VERSION 5.7 ;
  NOWIREEXTENSIONATPIN ON ;
  DIVIDERCHAR "/" ;
  BUSBITCHARS "[]" ;
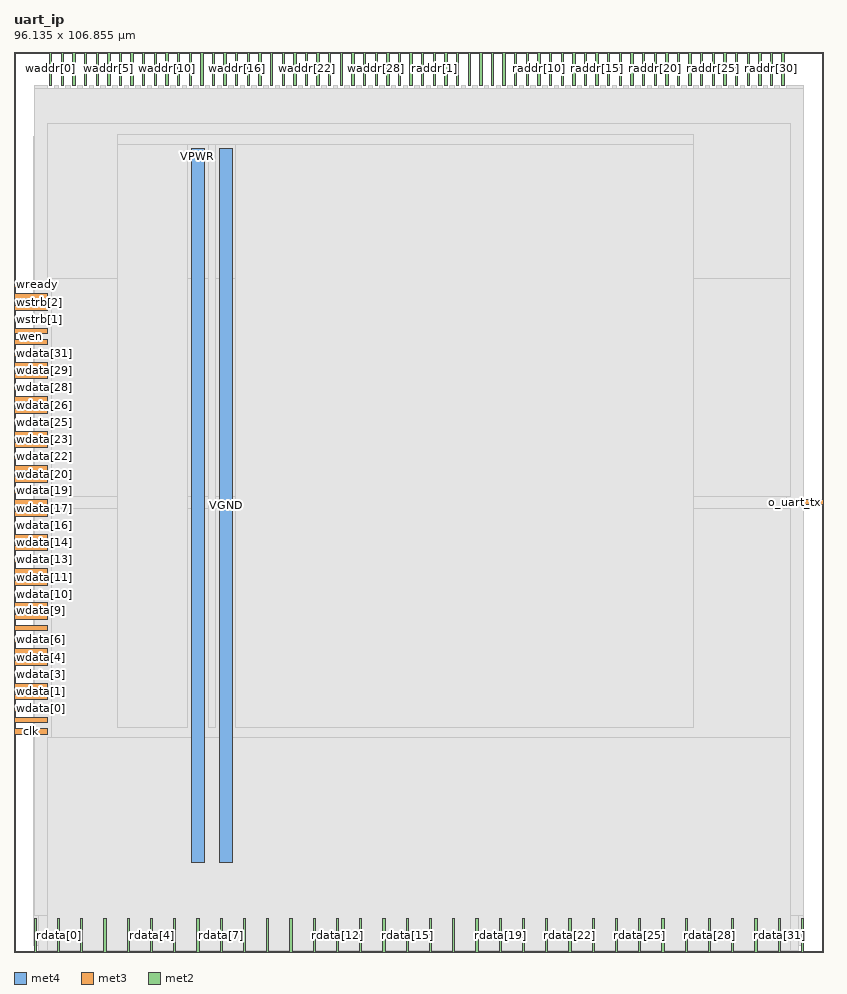
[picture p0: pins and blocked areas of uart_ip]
MACRO uart_ip
  CLASS BLOCK ;
  FOREIGN uart_ip ;
  ORIGIN 0.000 0.000 ;
  SIZE 96.135 BY 106.855 ;
  PIN VGND
    DIRECTION INOUT ;
    USE GROUND ;
    PORT
      LAYER met4 ;
        RECT 24.340 10.640 25.940 95.440 ;
    END
  END VGND
  PIN VPWR
    DIRECTION INOUT ;
    USE POWER ;
    PORT
      LAYER met4 ;
        RECT 21.040 10.640 22.640 95.440 ;
    END
  END VPWR
  PIN clk
    DIRECTION INPUT ;
    USE SIGNAL ;
    ANTENNAGATEAREA 1.286700 ;
    ANTENNADIFFAREA 0.434700 ;
    PORT
      LAYER met3 ;
        RECT 0.000 25.880 4.000 26.480 ;
    END
  END clk
  PIN o_uart_tx
    DIRECTION OUTPUT ;
    USE SIGNAL ;
    ANTENNAGATEAREA 0.434700 ;
    ANTENNADIFFAREA 0.880200 ;
    PORT
      LAYER met3 ;
        RECT 92.135 53.080 96.135 53.680 ;
    END
  END o_uart_tx
  PIN raddr[0]
    DIRECTION INPUT ;
    USE SIGNAL ;
    ANTENNAGATEAREA 0.631200 ;
    ANTENNADIFFAREA 0.434700 ;
    PORT
      LAYER met2 ;
        RECT 48.390 102.855 48.670 106.855 ;
    END
  END raddr[0]
  PIN raddr[10]
    DIRECTION INPUT ;
    USE SIGNAL ;
    ANTENNAGATEAREA 0.631200 ;
    ANTENNADIFFAREA 0.434700 ;
    PORT
      LAYER met2 ;
        RECT 62.190 102.855 62.470 106.855 ;
    END
  END raddr[10]
  PIN raddr[11]
    DIRECTION INPUT ;
    USE SIGNAL ;
    ANTENNAGATEAREA 0.631200 ;
    ANTENNADIFFAREA 0.434700 ;
    PORT
      LAYER met2 ;
        RECT 63.570 102.855 63.850 106.855 ;
    END
  END raddr[11]
  PIN raddr[12]
    DIRECTION INPUT ;
    USE SIGNAL ;
    ANTENNAGATEAREA 0.631200 ;
    ANTENNADIFFAREA 0.434700 ;
    PORT
      LAYER met2 ;
        RECT 64.950 102.855 65.230 106.855 ;
    END
  END raddr[12]
  PIN raddr[13]
    DIRECTION INPUT ;
    USE SIGNAL ;
    ANTENNAGATEAREA 0.631200 ;
    ANTENNADIFFAREA 0.434700 ;
    PORT
      LAYER met2 ;
        RECT 66.330 102.855 66.610 106.855 ;
    END
  END raddr[13]
  PIN raddr[14]
    DIRECTION INPUT ;
    USE SIGNAL ;
    ANTENNAGATEAREA 0.631200 ;
    ANTENNADIFFAREA 0.434700 ;
    PORT
      LAYER met2 ;
        RECT 67.710 102.855 67.990 106.855 ;
    END
  END raddr[14]
  PIN raddr[15]
    DIRECTION INPUT ;
    USE SIGNAL ;
    ANTENNAGATEAREA 0.631200 ;
    ANTENNADIFFAREA 0.434700 ;
    PORT
      LAYER met2 ;
        RECT 69.090 102.855 69.370 106.855 ;
    END
  END raddr[15]
  PIN raddr[16]
    DIRECTION INPUT ;
    USE SIGNAL ;
    ANTENNAGATEAREA 0.560700 ;
    ANTENNADIFFAREA 0.434700 ;
    PORT
      LAYER met2 ;
        RECT 70.470 102.855 70.750 106.855 ;
    END
  END raddr[16]
  PIN raddr[17]
    DIRECTION INPUT ;
    USE SIGNAL ;
    ANTENNAGATEAREA 0.631200 ;
    ANTENNADIFFAREA 0.434700 ;
    PORT
      LAYER met2 ;
        RECT 71.850 102.855 72.130 106.855 ;
    END
  END raddr[17]
  PIN raddr[18]
    DIRECTION INPUT ;
    USE SIGNAL ;
    ANTENNAGATEAREA 0.631200 ;
    ANTENNADIFFAREA 0.434700 ;
    PORT
      LAYER met2 ;
        RECT 73.230 102.855 73.510 106.855 ;
    END
  END raddr[18]
  PIN raddr[19]
    DIRECTION INPUT ;
    USE SIGNAL ;
    ANTENNAGATEAREA 0.631200 ;
    ANTENNADIFFAREA 0.434700 ;
    PORT
      LAYER met2 ;
        RECT 74.610 102.855 74.890 106.855 ;
    END
  END raddr[19]
  PIN raddr[1]
    DIRECTION INPUT ;
    USE SIGNAL ;
    ANTENNAGATEAREA 0.631200 ;
    ANTENNADIFFAREA 0.434700 ;
    PORT
      LAYER met2 ;
        RECT 49.770 102.855 50.050 106.855 ;
    END
  END raddr[1]
  PIN raddr[20]
    DIRECTION INPUT ;
    USE SIGNAL ;
    ANTENNAGATEAREA 0.631200 ;
    ANTENNADIFFAREA 0.434700 ;
    PORT
      LAYER met2 ;
        RECT 75.990 102.855 76.270 106.855 ;
    END
  END raddr[20]
  PIN raddr[21]
    DIRECTION INPUT ;
    USE SIGNAL ;
    ANTENNAGATEAREA 0.631200 ;
    ANTENNADIFFAREA 0.434700 ;
    PORT
      LAYER met2 ;
        RECT 77.370 102.855 77.650 106.855 ;
    END
  END raddr[21]
  PIN raddr[22]
    DIRECTION INPUT ;
    USE SIGNAL ;
    ANTENNAGATEAREA 0.631200 ;
    ANTENNADIFFAREA 0.434700 ;
    PORT
      LAYER met2 ;
        RECT 78.750 102.855 79.030 106.855 ;
    END
  END raddr[22]
  PIN raddr[23]
    DIRECTION INPUT ;
    USE SIGNAL ;
    ANTENNAGATEAREA 0.631200 ;
    ANTENNADIFFAREA 0.434700 ;
    PORT
      LAYER met2 ;
        RECT 80.130 102.855 80.410 106.855 ;
    END
  END raddr[23]
  PIN raddr[24]
    DIRECTION INPUT ;
    USE SIGNAL ;
    ANTENNAGATEAREA 0.631200 ;
    ANTENNADIFFAREA 0.434700 ;
    PORT
      LAYER met2 ;
        RECT 81.510 102.855 81.790 106.855 ;
    END
  END raddr[24]
  PIN raddr[25]
    DIRECTION INPUT ;
    USE SIGNAL ;
    ANTENNAGATEAREA 0.631200 ;
    ANTENNADIFFAREA 0.434700 ;
    PORT
      LAYER met2 ;
        RECT 82.890 102.855 83.170 106.855 ;
    END
  END raddr[25]
  PIN raddr[26]
    DIRECTION INPUT ;
    USE SIGNAL ;
    ANTENNAGATEAREA 0.631200 ;
    ANTENNADIFFAREA 0.434700 ;
    PORT
      LAYER met2 ;
        RECT 84.270 102.855 84.550 106.855 ;
    END
  END raddr[26]
  PIN raddr[27]
    DIRECTION INPUT ;
    USE SIGNAL ;
    ANTENNAGATEAREA 0.631200 ;
    ANTENNADIFFAREA 0.434700 ;
    PORT
      LAYER met2 ;
        RECT 85.650 102.855 85.930 106.855 ;
    END
  END raddr[27]
  PIN raddr[28]
    DIRECTION INPUT ;
    USE SIGNAL ;
    ANTENNAGATEAREA 0.631200 ;
    ANTENNADIFFAREA 0.434700 ;
    PORT
      LAYER met2 ;
        RECT 87.030 102.855 87.310 106.855 ;
    END
  END raddr[28]
  PIN raddr[29]
    DIRECTION INPUT ;
    USE SIGNAL ;
    ANTENNAGATEAREA 0.631200 ;
    ANTENNADIFFAREA 0.434700 ;
    PORT
      LAYER met2 ;
        RECT 88.410 102.855 88.690 106.855 ;
    END
  END raddr[29]
  PIN raddr[2]
    DIRECTION INPUT ;
    USE SIGNAL ;
    ANTENNAGATEAREA 0.560700 ;
    ANTENNADIFFAREA 0.434700 ;
    PORT
      LAYER met2 ;
        RECT 51.150 102.855 51.430 106.855 ;
    END
  END raddr[2]
  PIN raddr[30]
    DIRECTION INPUT ;
    USE SIGNAL ;
    ANTENNAGATEAREA 0.631200 ;
    ANTENNADIFFAREA 0.434700 ;
    PORT
      LAYER met2 ;
        RECT 89.790 102.855 90.070 106.855 ;
    END
  END raddr[30]
  PIN raddr[31]
    DIRECTION INPUT ;
    USE SIGNAL ;
    ANTENNAGATEAREA 0.631200 ;
    ANTENNADIFFAREA 0.434700 ;
    PORT
      LAYER met2 ;
        RECT 91.170 102.855 91.450 106.855 ;
    END
  END raddr[31]
  PIN raddr[3]
    DIRECTION INPUT ;
    USE SIGNAL ;
    ANTENNAGATEAREA 0.631200 ;
    ANTENNADIFFAREA 0.434700 ;
    PORT
      LAYER met2 ;
        RECT 52.530 102.855 52.810 106.855 ;
    END
  END raddr[3]
  PIN raddr[4]
    DIRECTION INPUT ;
    USE SIGNAL ;
    ANTENNAGATEAREA 0.631200 ;
    ANTENNADIFFAREA 0.434700 ;
    PORT
      LAYER met2 ;
        RECT 53.910 102.855 54.190 106.855 ;
    END
  END raddr[4]
  PIN raddr[5]
    DIRECTION INPUT ;
    USE SIGNAL ;
    ANTENNAGATEAREA 0.631200 ;
    ANTENNADIFFAREA 0.434700 ;
    PORT
      LAYER met2 ;
        RECT 55.290 102.855 55.570 106.855 ;
    END
  END raddr[5]
  PIN raddr[6]
    DIRECTION INPUT ;
    USE SIGNAL ;
    ANTENNAGATEAREA 0.631200 ;
    ANTENNADIFFAREA 0.434700 ;
    PORT
      LAYER met2 ;
        RECT 56.670 102.855 56.950 106.855 ;
    END
  END raddr[6]
  PIN raddr[7]
    DIRECTION INPUT ;
    USE SIGNAL ;
    ANTENNAGATEAREA 0.631200 ;
    ANTENNADIFFAREA 0.434700 ;
    PORT
      LAYER met2 ;
        RECT 58.050 102.855 58.330 106.855 ;
    END
  END raddr[7]
  PIN raddr[8]
    DIRECTION INPUT ;
    USE SIGNAL ;
    ANTENNAGATEAREA 0.560700 ;
    ANTENNADIFFAREA 0.434700 ;
    PORT
      LAYER met2 ;
        RECT 59.430 102.855 59.710 106.855 ;
    END
  END raddr[8]
  PIN raddr[9]
    DIRECTION INPUT ;
    USE SIGNAL ;
    ANTENNAGATEAREA 0.631200 ;
    ANTENNADIFFAREA 0.434700 ;
    PORT
      LAYER met2 ;
        RECT 60.810 102.855 61.090 106.855 ;
    END
  END raddr[9]
  PIN rdata[0]
    DIRECTION OUTPUT ;
    USE SIGNAL ;
    ANTENNAGATEAREA 0.434700 ;
    ANTENNADIFFAREA 0.880200 ;
    PORT
      LAYER met2 ;
        RECT 5.150 0.000 5.430 4.000 ;
    END
  END rdata[0]
  PIN rdata[10]
    DIRECTION OUTPUT ;
    USE SIGNAL ;
    ANTENNAGATEAREA 0.434700 ;
    ANTENNADIFFAREA 0.434700 ;
    PORT
      LAYER met2 ;
        RECT 32.750 0.000 33.030 4.000 ;
    END
  END rdata[10]
  PIN rdata[11]
    DIRECTION OUTPUT ;
    USE SIGNAL ;
    ANTENNAGATEAREA 0.434700 ;
    ANTENNADIFFAREA 0.434700 ;
    PORT
      LAYER met2 ;
        RECT 35.510 0.000 35.790 4.000 ;
    END
  END rdata[11]
  PIN rdata[12]
    DIRECTION OUTPUT ;
    USE SIGNAL ;
    ANTENNAGATEAREA 0.434700 ;
    ANTENNADIFFAREA 0.434700 ;
    PORT
      LAYER met2 ;
        RECT 38.270 0.000 38.550 4.000 ;
    END
  END rdata[12]
  PIN rdata[13]
    DIRECTION OUTPUT ;
    USE SIGNAL ;
    ANTENNAGATEAREA 0.434700 ;
    ANTENNADIFFAREA 0.880200 ;
    PORT
      LAYER met2 ;
        RECT 41.030 0.000 41.310 4.000 ;
    END
  END rdata[13]
  PIN rdata[14]
    DIRECTION OUTPUT ;
    USE SIGNAL ;
    ANTENNAGATEAREA 0.434700 ;
    ANTENNADIFFAREA 0.434700 ;
    PORT
      LAYER met2 ;
        RECT 43.790 0.000 44.070 4.000 ;
    END
  END rdata[14]
  PIN rdata[15]
    DIRECTION OUTPUT ;
    USE SIGNAL ;
    ANTENNAGATEAREA 0.434700 ;
    ANTENNADIFFAREA 0.434700 ;
    PORT
      LAYER met2 ;
        RECT 46.550 0.000 46.830 4.000 ;
    END
  END rdata[15]
  PIN rdata[16]
    DIRECTION OUTPUT ;
    USE SIGNAL ;
    ANTENNAGATEAREA 0.434700 ;
    ANTENNADIFFAREA 0.434700 ;
    PORT
      LAYER met2 ;
        RECT 49.310 0.000 49.590 4.000 ;
    END
  END rdata[16]
  PIN rdata[17]
    DIRECTION OUTPUT ;
    USE SIGNAL ;
    ANTENNAGATEAREA 0.434700 ;
    ANTENNADIFFAREA 0.434700 ;
    PORT
      LAYER met2 ;
        RECT 52.070 0.000 52.350 4.000 ;
    END
  END rdata[17]
  PIN rdata[18]
    DIRECTION OUTPUT ;
    USE SIGNAL ;
    ANTENNAGATEAREA 0.434700 ;
    ANTENNADIFFAREA 0.434700 ;
    PORT
      LAYER met2 ;
        RECT 54.830 0.000 55.110 4.000 ;
    END
  END rdata[18]
  PIN rdata[19]
    DIRECTION OUTPUT ;
    USE SIGNAL ;
    ANTENNAGATEAREA 0.434700 ;
    ANTENNADIFFAREA 0.434700 ;
    PORT
      LAYER met2 ;
        RECT 57.590 0.000 57.870 4.000 ;
    END
  END rdata[19]
  PIN rdata[1]
    DIRECTION OUTPUT ;
    USE SIGNAL ;
    ANTENNAGATEAREA 0.434700 ;
    ANTENNADIFFAREA 0.880200 ;
    PORT
      LAYER met2 ;
        RECT 7.910 0.000 8.190 4.000 ;
    END
  END rdata[1]
  PIN rdata[20]
    DIRECTION OUTPUT ;
    USE SIGNAL ;
    ANTENNAGATEAREA 0.434700 ;
    ANTENNADIFFAREA 0.434700 ;
    PORT
      LAYER met2 ;
        RECT 60.350 0.000 60.630 4.000 ;
    END
  END rdata[20]
  PIN rdata[21]
    DIRECTION OUTPUT ;
    USE SIGNAL ;
    ANTENNAGATEAREA 0.434700 ;
    ANTENNADIFFAREA 0.434700 ;
    PORT
      LAYER met2 ;
        RECT 63.110 0.000 63.390 4.000 ;
    END
  END rdata[21]
  PIN rdata[22]
    DIRECTION OUTPUT ;
    USE SIGNAL ;
    ANTENNAGATEAREA 0.434700 ;
    ANTENNADIFFAREA 0.434700 ;
    PORT
      LAYER met2 ;
        RECT 65.870 0.000 66.150 4.000 ;
    END
  END rdata[22]
  PIN rdata[23]
    DIRECTION OUTPUT ;
    USE SIGNAL ;
    ANTENNAGATEAREA 0.434700 ;
    ANTENNADIFFAREA 0.434700 ;
    PORT
      LAYER met2 ;
        RECT 68.630 0.000 68.910 4.000 ;
    END
  END rdata[23]
  PIN rdata[24]
    DIRECTION OUTPUT ;
    USE SIGNAL ;
    ANTENNAGATEAREA 0.434700 ;
    ANTENNADIFFAREA 0.434700 ;
    PORT
      LAYER met2 ;
        RECT 71.390 0.000 71.670 4.000 ;
    END
  END rdata[24]
  PIN rdata[25]
    DIRECTION OUTPUT ;
    USE SIGNAL ;
    ANTENNAGATEAREA 0.434700 ;
    ANTENNADIFFAREA 0.434700 ;
    PORT
      LAYER met2 ;
        RECT 74.150 0.000 74.430 4.000 ;
    END
  END rdata[25]
  PIN rdata[26]
    DIRECTION OUTPUT ;
    USE SIGNAL ;
    ANTENNAGATEAREA 0.434700 ;
    ANTENNADIFFAREA 0.434700 ;
    PORT
      LAYER met2 ;
        RECT 76.910 0.000 77.190 4.000 ;
    END
  END rdata[26]
  PIN rdata[27]
    DIRECTION OUTPUT ;
    USE SIGNAL ;
    ANTENNAGATEAREA 0.434700 ;
    ANTENNADIFFAREA 0.434700 ;
    PORT
      LAYER met2 ;
        RECT 79.670 0.000 79.950 4.000 ;
    END
  END rdata[27]
  PIN rdata[28]
    DIRECTION OUTPUT ;
    USE SIGNAL ;
    ANTENNAGATEAREA 0.434700 ;
    ANTENNADIFFAREA 0.434700 ;
    PORT
      LAYER met2 ;
        RECT 82.430 0.000 82.710 4.000 ;
    END
  END rdata[28]
  PIN rdata[29]
    DIRECTION OUTPUT ;
    USE SIGNAL ;
    ANTENNAGATEAREA 0.434700 ;
    ANTENNADIFFAREA 0.434700 ;
    PORT
      LAYER met2 ;
        RECT 85.190 0.000 85.470 4.000 ;
    END
  END rdata[29]
  PIN rdata[2]
    DIRECTION OUTPUT ;
    USE SIGNAL ;
    ANTENNAGATEAREA 0.434700 ;
    ANTENNADIFFAREA 0.880200 ;
    PORT
      LAYER met2 ;
        RECT 10.670 0.000 10.950 4.000 ;
    END
  END rdata[2]
  PIN rdata[30]
    DIRECTION OUTPUT ;
    USE SIGNAL ;
    ANTENNAGATEAREA 0.434700 ;
    ANTENNADIFFAREA 0.434700 ;
    PORT
      LAYER met2 ;
        RECT 87.950 0.000 88.230 4.000 ;
    END
  END rdata[30]
  PIN rdata[31]
    DIRECTION OUTPUT ;
    USE SIGNAL ;
    ANTENNAGATEAREA 0.434700 ;
    ANTENNADIFFAREA 0.434700 ;
    PORT
      LAYER met2 ;
        RECT 90.710 0.000 90.990 4.000 ;
    END
  END rdata[31]
  PIN rdata[3]
    DIRECTION OUTPUT ;
    USE SIGNAL ;
    ANTENNAGATEAREA 0.434700 ;
    ANTENNADIFFAREA 0.880200 ;
    PORT
      LAYER met2 ;
        RECT 13.430 0.000 13.710 4.000 ;
    END
  END rdata[3]
  PIN rdata[4]
    DIRECTION OUTPUT ;
    USE SIGNAL ;
    ANTENNAGATEAREA 0.434700 ;
    ANTENNADIFFAREA 0.880200 ;
    PORT
      LAYER met2 ;
        RECT 16.190 0.000 16.470 4.000 ;
    END
  END rdata[4]
  PIN rdata[5]
    DIRECTION OUTPUT ;
    USE SIGNAL ;
    ANTENNAGATEAREA 0.434700 ;
    ANTENNADIFFAREA 0.880200 ;
    PORT
      LAYER met2 ;
        RECT 18.950 0.000 19.230 4.000 ;
    END
  END rdata[5]
  PIN rdata[6]
    DIRECTION OUTPUT ;
    USE SIGNAL ;
    ANTENNAGATEAREA 0.434700 ;
    ANTENNADIFFAREA 0.880200 ;
    PORT
      LAYER met2 ;
        RECT 21.710 0.000 21.990 4.000 ;
    END
  END rdata[6]
  PIN rdata[7]
    DIRECTION OUTPUT ;
    USE SIGNAL ;
    ANTENNAGATEAREA 0.434700 ;
    ANTENNADIFFAREA 0.880200 ;
    PORT
      LAYER met2 ;
        RECT 24.470 0.000 24.750 4.000 ;
    END
  END rdata[7]
  PIN rdata[8]
    DIRECTION OUTPUT ;
    USE SIGNAL ;
    ANTENNAGATEAREA 0.434700 ;
    ANTENNADIFFAREA 0.434700 ;
    PORT
      LAYER met2 ;
        RECT 27.230 0.000 27.510 4.000 ;
    END
  END rdata[8]
  PIN rdata[9]
    DIRECTION OUTPUT ;
    USE SIGNAL ;
    ANTENNAGATEAREA 0.434700 ;
    ANTENNADIFFAREA 0.434700 ;
    PORT
      LAYER met2 ;
        RECT 29.990 0.000 30.270 4.000 ;
    END
  END rdata[9]
  PIN ren
    DIRECTION INPUT ;
    USE SIGNAL ;
    ANTENNAGATEAREA 0.560700 ;
    ANTENNADIFFAREA 0.434700 ;
    PORT
      LAYER met2 ;
        RECT 2.390 0.000 2.670 4.000 ;
    END
  END ren
  PIN rst
    DIRECTION INPUT ;
    USE SIGNAL ;
    ANTENNAGATEAREA 0.560700 ;
    ANTENNADIFFAREA 0.434700 ;
    PORT
      LAYER met3 ;
        RECT 0.000 27.240 4.000 27.840 ;
    END
  END rst
  PIN rvalid
    DIRECTION OUTPUT ;
    USE SIGNAL ;
    ANTENNAGATEAREA 0.434700 ;
    ANTENNADIFFAREA 0.880200 ;
    PORT
      LAYER met2 ;
        RECT 93.470 0.000 93.750 4.000 ;
    END
  END rvalid
  PIN waddr[0]
    DIRECTION INPUT ;
    USE SIGNAL ;
    ANTENNAGATEAREA 0.631200 ;
    ANTENNADIFFAREA 0.434700 ;
    PORT
      LAYER met2 ;
        RECT 4.230 102.855 4.510 106.855 ;
    END
  END waddr[0]
  PIN waddr[10]
    DIRECTION INPUT ;
    USE SIGNAL ;
    ANTENNAGATEAREA 0.631200 ;
    ANTENNADIFFAREA 0.434700 ;
    PORT
      LAYER met2 ;
        RECT 18.030 102.855 18.310 106.855 ;
    END
  END waddr[10]
  PIN waddr[11]
    DIRECTION INPUT ;
    USE SIGNAL ;
    ANTENNAGATEAREA 0.560700 ;
    ANTENNADIFFAREA 0.434700 ;
    PORT
      LAYER met2 ;
        RECT 19.410 102.855 19.690 106.855 ;
    END
  END waddr[11]
  PIN waddr[12]
    DIRECTION INPUT ;
    USE SIGNAL ;
    ANTENNAGATEAREA 0.631200 ;
    ANTENNADIFFAREA 0.434700 ;
    PORT
      LAYER met2 ;
        RECT 20.790 102.855 21.070 106.855 ;
    END
  END waddr[12]
  PIN waddr[13]
    DIRECTION INPUT ;
    USE SIGNAL ;
    ANTENNAGATEAREA 0.631200 ;
    ANTENNADIFFAREA 0.434700 ;
    PORT
      LAYER met2 ;
        RECT 22.170 102.855 22.450 106.855 ;
    END
  END waddr[13]
  PIN waddr[14]
    DIRECTION INPUT ;
    USE SIGNAL ;
    ANTENNAGATEAREA 0.631200 ;
    ANTENNADIFFAREA 0.434700 ;
    PORT
      LAYER met2 ;
        RECT 23.550 102.855 23.830 106.855 ;
    END
  END waddr[14]
  PIN waddr[15]
    DIRECTION INPUT ;
    USE SIGNAL ;
    ANTENNAGATEAREA 0.631200 ;
    ANTENNADIFFAREA 0.434700 ;
    PORT
      LAYER met2 ;
        RECT 24.930 102.855 25.210 106.855 ;
    END
  END waddr[15]
  PIN waddr[16]
    DIRECTION INPUT ;
    USE SIGNAL ;
    ANTENNAGATEAREA 0.631200 ;
    ANTENNADIFFAREA 0.434700 ;
    PORT
      LAYER met2 ;
        RECT 26.310 102.855 26.590 106.855 ;
    END
  END waddr[16]
  PIN waddr[17]
    DIRECTION INPUT ;
    USE SIGNAL ;
    ANTENNAGATEAREA 0.631200 ;
    ANTENNADIFFAREA 0.434700 ;
    PORT
      LAYER met2 ;
        RECT 27.690 102.855 27.970 106.855 ;
    END
  END waddr[17]
  PIN waddr[18]
    DIRECTION INPUT ;
    USE SIGNAL ;
    ANTENNAGATEAREA 0.631200 ;
    ANTENNADIFFAREA 0.434700 ;
    PORT
      LAYER met2 ;
        RECT 29.070 102.855 29.350 106.855 ;
    END
  END waddr[18]
  PIN waddr[19]
    DIRECTION INPUT ;
    USE SIGNAL ;
    ANTENNAGATEAREA 0.631200 ;
    ANTENNADIFFAREA 0.434700 ;
    PORT
      LAYER met2 ;
        RECT 30.450 102.855 30.730 106.855 ;
    END
  END waddr[19]
  PIN waddr[1]
    DIRECTION INPUT ;
    USE SIGNAL ;
    ANTENNAGATEAREA 0.631200 ;
    ANTENNADIFFAREA 0.434700 ;
    PORT
      LAYER met2 ;
        RECT 5.610 102.855 5.890 106.855 ;
    END
  END waddr[1]
  PIN waddr[20]
    DIRECTION INPUT ;
    USE SIGNAL ;
    ANTENNAGATEAREA 0.631200 ;
    ANTENNADIFFAREA 0.434700 ;
    PORT
      LAYER met2 ;
        RECT 31.830 102.855 32.110 106.855 ;
    END
  END waddr[20]
  PIN waddr[21]
    DIRECTION INPUT ;
    USE SIGNAL ;
    ANTENNAGATEAREA 0.631200 ;
    ANTENNADIFFAREA 0.434700 ;
    PORT
      LAYER met2 ;
        RECT 33.210 102.855 33.490 106.855 ;
    END
  END waddr[21]
  PIN waddr[22]
    DIRECTION INPUT ;
    USE SIGNAL ;
    ANTENNAGATEAREA 0.631200 ;
    ANTENNADIFFAREA 0.434700 ;
    PORT
      LAYER met2 ;
        RECT 34.590 102.855 34.870 106.855 ;
    END
  END waddr[22]
  PIN waddr[23]
    DIRECTION INPUT ;
    USE SIGNAL ;
    ANTENNAGATEAREA 0.631200 ;
    ANTENNADIFFAREA 0.434700 ;
    PORT
      LAYER met2 ;
        RECT 35.970 102.855 36.250 106.855 ;
    END
  END waddr[23]
  PIN waddr[24]
    DIRECTION INPUT ;
    USE SIGNAL ;
    ANTENNAGATEAREA 0.631200 ;
    ANTENNADIFFAREA 0.434700 ;
    PORT
      LAYER met2 ;
        RECT 37.350 102.855 37.630 106.855 ;
    END
  END waddr[24]
  PIN waddr[25]
    DIRECTION INPUT ;
    USE SIGNAL ;
    ANTENNAGATEAREA 0.631200 ;
    ANTENNADIFFAREA 0.434700 ;
    PORT
      LAYER met2 ;
        RECT 38.730 102.855 39.010 106.855 ;
    END
  END waddr[25]
  PIN waddr[26]
    DIRECTION INPUT ;
    USE SIGNAL ;
    ANTENNAGATEAREA 0.631200 ;
    ANTENNADIFFAREA 0.434700 ;
    PORT
      LAYER met2 ;
        RECT 40.110 102.855 40.390 106.855 ;
    END
  END waddr[26]
  PIN waddr[27]
    DIRECTION INPUT ;
    USE SIGNAL ;
    ANTENNAGATEAREA 0.631200 ;
    ANTENNADIFFAREA 0.434700 ;
    PORT
      LAYER met2 ;
        RECT 41.490 102.855 41.770 106.855 ;
    END
  END waddr[27]
  PIN waddr[28]
    DIRECTION INPUT ;
    USE SIGNAL ;
    ANTENNAGATEAREA 0.631200 ;
    ANTENNADIFFAREA 0.434700 ;
    PORT
      LAYER met2 ;
        RECT 42.870 102.855 43.150 106.855 ;
    END
  END waddr[28]
  PIN waddr[29]
    DIRECTION INPUT ;
    USE SIGNAL ;
    ANTENNAGATEAREA 0.631200 ;
    ANTENNADIFFAREA 0.434700 ;
    PORT
      LAYER met2 ;
        RECT 44.250 102.855 44.530 106.855 ;
    END
  END waddr[29]
  PIN waddr[2]
    DIRECTION INPUT ;
    USE SIGNAL ;
    ANTENNAGATEAREA 0.631200 ;
    ANTENNADIFFAREA 0.434700 ;
    PORT
      LAYER met2 ;
        RECT 6.990 102.855 7.270 106.855 ;
    END
  END waddr[2]
  PIN waddr[30]
    DIRECTION INPUT ;
    USE SIGNAL ;
    ANTENNAGATEAREA 0.631200 ;
    ANTENNADIFFAREA 0.434700 ;
    PORT
      LAYER met2 ;
        RECT 45.630 102.855 45.910 106.855 ;
    END
  END waddr[30]
  PIN waddr[31]
    DIRECTION INPUT ;
    USE SIGNAL ;
    ANTENNAGATEAREA 0.631200 ;
    ANTENNADIFFAREA 0.434700 ;
    PORT
      LAYER met2 ;
        RECT 47.010 102.855 47.290 106.855 ;
    END
  END waddr[31]
  PIN waddr[3]
    DIRECTION INPUT ;
    USE SIGNAL ;
    ANTENNAGATEAREA 0.631200 ;
    ANTENNADIFFAREA 0.434700 ;
    PORT
      LAYER met2 ;
        RECT 8.370 102.855 8.650 106.855 ;
    END
  END waddr[3]
  PIN waddr[4]
    DIRECTION INPUT ;
    USE SIGNAL ;
    ANTENNAGATEAREA 0.631200 ;
    ANTENNADIFFAREA 0.434700 ;
    PORT
      LAYER met2 ;
        RECT 9.750 102.855 10.030 106.855 ;
    END
  END waddr[4]
  PIN waddr[5]
    DIRECTION INPUT ;
    USE SIGNAL ;
    ANTENNAGATEAREA 0.631200 ;
    ANTENNADIFFAREA 0.434700 ;
    PORT
      LAYER met2 ;
        RECT 11.130 102.855 11.410 106.855 ;
    END
  END waddr[5]
  PIN waddr[6]
    DIRECTION INPUT ;
    USE SIGNAL ;
    ANTENNAGATEAREA 0.631200 ;
    ANTENNADIFFAREA 0.434700 ;
    PORT
      LAYER met2 ;
        RECT 12.510 102.855 12.790 106.855 ;
    END
  END waddr[6]
  PIN waddr[7]
    DIRECTION INPUT ;
    USE SIGNAL ;
    ANTENNAGATEAREA 0.631200 ;
    ANTENNADIFFAREA 0.434700 ;
    PORT
      LAYER met2 ;
        RECT 13.890 102.855 14.170 106.855 ;
    END
  END waddr[7]
  PIN waddr[8]
    DIRECTION INPUT ;
    USE SIGNAL ;
    ANTENNAGATEAREA 0.631200 ;
    ANTENNADIFFAREA 0.434700 ;
    PORT
      LAYER met2 ;
        RECT 15.270 102.855 15.550 106.855 ;
    END
  END waddr[8]
  PIN waddr[9]
    DIRECTION INPUT ;
    USE SIGNAL ;
    ANTENNAGATEAREA 0.631200 ;
    ANTENNADIFFAREA 0.434700 ;
    PORT
      LAYER met2 ;
        RECT 16.650 102.855 16.930 106.855 ;
    END
  END waddr[9]
  PIN wdata[0]
    DIRECTION INPUT ;
    USE SIGNAL ;
    ANTENNAGATEAREA 0.560700 ;
    ANTENNADIFFAREA 0.434700 ;
    PORT
      LAYER met3 ;
        RECT 0.000 28.600 4.000 29.200 ;
    END
  END wdata[0]
  PIN wdata[10]
    DIRECTION INPUT ;
    USE SIGNAL ;
    PORT
      LAYER met3 ;
        RECT 0.000 42.200 4.000 42.800 ;
    END
  END wdata[10]
  PIN wdata[11]
    DIRECTION INPUT ;
    USE SIGNAL ;
    PORT
      LAYER met3 ;
        RECT 0.000 43.560 4.000 44.160 ;
    END
  END wdata[11]
  PIN wdata[12]
    DIRECTION INPUT ;
    USE SIGNAL ;
    PORT
      LAYER met3 ;
        RECT 0.000 44.920 4.000 45.520 ;
    END
  END wdata[12]
  PIN wdata[13]
    DIRECTION INPUT ;
    USE SIGNAL ;
    PORT
      LAYER met3 ;
        RECT 0.000 46.280 4.000 46.880 ;
    END
  END wdata[13]
  PIN wdata[14]
    DIRECTION INPUT ;
    USE SIGNAL ;
    PORT
      LAYER met3 ;
        RECT 0.000 47.640 4.000 48.240 ;
    END
  END wdata[14]
  PIN wdata[15]
    DIRECTION INPUT ;
    USE SIGNAL ;
    PORT
      LAYER met3 ;
        RECT 0.000 49.000 4.000 49.600 ;
    END
  END wdata[15]
  PIN wdata[16]
    DIRECTION INPUT ;
    USE SIGNAL ;
    PORT
      LAYER met3 ;
        RECT 0.000 50.360 4.000 50.960 ;
    END
  END wdata[16]
  PIN wdata[17]
    DIRECTION INPUT ;
    USE SIGNAL ;
    PORT
      LAYER met3 ;
        RECT 0.000 51.720 4.000 52.320 ;
    END
  END wdata[17]
  PIN wdata[18]
    DIRECTION INPUT ;
    USE SIGNAL ;
    PORT
      LAYER met3 ;
        RECT 0.000 53.080 4.000 53.680 ;
    END
  END wdata[18]
  PIN wdata[19]
    DIRECTION INPUT ;
    USE SIGNAL ;
    PORT
      LAYER met3 ;
        RECT 0.000 54.440 4.000 55.040 ;
    END
  END wdata[19]
  PIN wdata[1]
    DIRECTION INPUT ;
    USE SIGNAL ;
    ANTENNAGATEAREA 0.560700 ;
    ANTENNADIFFAREA 0.434700 ;
    PORT
      LAYER met3 ;
        RECT 0.000 29.960 4.000 30.560 ;
    END
  END wdata[1]
  PIN wdata[20]
    DIRECTION INPUT ;
    USE SIGNAL ;
    PORT
      LAYER met3 ;
        RECT 0.000 55.800 4.000 56.400 ;
    END
  END wdata[20]
  PIN wdata[21]
    DIRECTION INPUT ;
    USE SIGNAL ;
    PORT
      LAYER met3 ;
        RECT 0.000 57.160 4.000 57.760 ;
    END
  END wdata[21]
  PIN wdata[22]
    DIRECTION INPUT ;
    USE SIGNAL ;
    PORT
      LAYER met3 ;
        RECT 0.000 58.520 4.000 59.120 ;
    END
  END wdata[22]
  PIN wdata[23]
    DIRECTION INPUT ;
    USE SIGNAL ;
    PORT
      LAYER met3 ;
        RECT 0.000 59.880 4.000 60.480 ;
    END
  END wdata[23]
  PIN wdata[24]
    DIRECTION INPUT ;
    USE SIGNAL ;
    PORT
      LAYER met3 ;
        RECT 0.000 61.240 4.000 61.840 ;
    END
  END wdata[24]
  PIN wdata[25]
    DIRECTION INPUT ;
    USE SIGNAL ;
    PORT
      LAYER met3 ;
        RECT 0.000 62.600 4.000 63.200 ;
    END
  END wdata[25]
  PIN wdata[26]
    DIRECTION INPUT ;
    USE SIGNAL ;
    PORT
      LAYER met3 ;
        RECT 0.000 63.960 4.000 64.560 ;
    END
  END wdata[26]
  PIN wdata[27]
    DIRECTION INPUT ;
    USE SIGNAL ;
    PORT
      LAYER met3 ;
        RECT 0.000 65.320 4.000 65.920 ;
    END
  END wdata[27]
  PIN wdata[28]
    DIRECTION INPUT ;
    USE SIGNAL ;
    PORT
      LAYER met3 ;
        RECT 0.000 66.680 4.000 67.280 ;
    END
  END wdata[28]
  PIN wdata[29]
    DIRECTION INPUT ;
    USE SIGNAL ;
    PORT
      LAYER met3 ;
        RECT 0.000 68.040 4.000 68.640 ;
    END
  END wdata[29]
  PIN wdata[2]
    DIRECTION INPUT ;
    USE SIGNAL ;
    ANTENNAGATEAREA 0.560700 ;
    ANTENNADIFFAREA 0.434700 ;
    PORT
      LAYER met3 ;
        RECT 0.000 31.320 4.000 31.920 ;
    END
  END wdata[2]
  PIN wdata[30]
    DIRECTION INPUT ;
    USE SIGNAL ;
    PORT
      LAYER met3 ;
        RECT 0.000 69.400 4.000 70.000 ;
    END
  END wdata[30]
  PIN wdata[31]
    DIRECTION INPUT ;
    USE SIGNAL ;
    PORT
      LAYER met3 ;
        RECT 0.000 70.760 4.000 71.360 ;
    END
  END wdata[31]
  PIN wdata[3]
    DIRECTION INPUT ;
    USE SIGNAL ;
    ANTENNAGATEAREA 0.560700 ;
    ANTENNADIFFAREA 0.434700 ;
    PORT
      LAYER met3 ;
        RECT 0.000 32.680 4.000 33.280 ;
    END
  END wdata[3]
  PIN wdata[4]
    DIRECTION INPUT ;
    USE SIGNAL ;
    ANTENNAGATEAREA 0.560700 ;
    ANTENNADIFFAREA 0.434700 ;
    PORT
      LAYER met3 ;
        RECT 0.000 34.040 4.000 34.640 ;
    END
  END wdata[4]
  PIN wdata[5]
    DIRECTION INPUT ;
    USE SIGNAL ;
    ANTENNAGATEAREA 0.560700 ;
    ANTENNADIFFAREA 0.434700 ;
    PORT
      LAYER met3 ;
        RECT 0.000 35.400 4.000 36.000 ;
    END
  END wdata[5]
  PIN wdata[6]
    DIRECTION INPUT ;
    USE SIGNAL ;
    ANTENNAGATEAREA 0.560700 ;
    ANTENNADIFFAREA 0.434700 ;
    PORT
      LAYER met3 ;
        RECT 0.000 36.760 4.000 37.360 ;
    END
  END wdata[6]
  PIN wdata[7]
    DIRECTION INPUT ;
    USE SIGNAL ;
    ANTENNAGATEAREA 0.560700 ;
    ANTENNADIFFAREA 0.434700 ;
    PORT
      LAYER met3 ;
        RECT 0.000 38.120 4.000 38.720 ;
    END
  END wdata[7]
  PIN wdata[8]
    DIRECTION INPUT ;
    USE SIGNAL ;
    PORT
      LAYER met3 ;
        RECT 0.000 39.480 4.000 40.080 ;
    END
  END wdata[8]
  PIN wdata[9]
    DIRECTION INPUT ;
    USE SIGNAL ;
    ANTENNAGATEAREA 0.631200 ;
    ANTENNADIFFAREA 0.434700 ;
    PORT
      LAYER met3 ;
        RECT 0.000 40.840 4.000 41.440 ;
    END
  END wdata[9]
  PIN wen
    DIRECTION INPUT ;
    USE SIGNAL ;
    ANTENNAGATEAREA 0.631200 ;
    ANTENNADIFFAREA 0.434700 ;
    PORT
      LAYER met3 ;
        RECT 0.000 72.120 4.000 72.720 ;
    END
  END wen
  PIN wready
    DIRECTION OUTPUT ;
    USE SIGNAL ;
    ANTENNAGATEAREA 0.434700 ;
    ANTENNADIFFAREA 0.434700 ;
    PORT
      LAYER met3 ;
        RECT 0.000 78.920 4.000 79.520 ;
    END
  END wready
  PIN wstrb[0]
    DIRECTION INPUT ;
    USE SIGNAL ;
    ANTENNAGATEAREA 0.631200 ;
    ANTENNADIFFAREA 0.434700 ;
    PORT
      LAYER met3 ;
        RECT 0.000 73.480 4.000 74.080 ;
    END
  END wstrb[0]
  PIN wstrb[1]
    DIRECTION INPUT ;
    USE SIGNAL ;
    ANTENNAGATEAREA 0.560700 ;
    ANTENNADIFFAREA 0.434700 ;
    PORT
      LAYER met3 ;
        RECT 0.000 74.840 4.000 75.440 ;
    END
  END wstrb[1]
  PIN wstrb[2]
    DIRECTION INPUT ;
    USE SIGNAL ;
    PORT
      LAYER met3 ;
        RECT 0.000 76.200 4.000 76.800 ;
    END
  END wstrb[2]
  PIN wstrb[3]
    DIRECTION INPUT ;
    USE SIGNAL ;
    PORT
      LAYER met3 ;
        RECT 0.000 77.560 4.000 78.160 ;
    END
  END wstrb[3]
  OBS
      LAYER nwell ;
        RECT 5.330 10.795 90.350 95.390 ;
      LAYER li1 ;
        RECT 5.520 10.795 90.160 95.285 ;
      LAYER met1 ;
        RECT 2.370 0.720 93.770 96.860 ;
      LAYER met2 ;
        RECT 2.400 102.575 3.950 102.855 ;
        RECT 4.790 102.575 5.330 102.855 ;
        RECT 6.170 102.575 6.710 102.855 ;
        RECT 7.550 102.575 8.090 102.855 ;
        RECT 8.930 102.575 9.470 102.855 ;
        RECT 10.310 102.575 10.850 102.855 ;
        RECT 11.690 102.575 12.230 102.855 ;
        RECT 13.070 102.575 13.610 102.855 ;
        RECT 14.450 102.575 14.990 102.855 ;
        RECT 15.830 102.575 16.370 102.855 ;
        RECT 17.210 102.575 17.750 102.855 ;
        RECT 18.590 102.575 19.130 102.855 ;
        RECT 19.970 102.575 20.510 102.855 ;
        RECT 21.350 102.575 21.890 102.855 ;
        RECT 22.730 102.575 23.270 102.855 ;
        RECT 24.110 102.575 24.650 102.855 ;
        RECT 25.490 102.575 26.030 102.855 ;
        RECT 26.870 102.575 27.410 102.855 ;
        RECT 28.250 102.575 28.790 102.855 ;
        RECT 29.630 102.575 30.170 102.855 ;
        RECT 31.010 102.575 31.550 102.855 ;
        RECT 32.390 102.575 32.930 102.855 ;
        RECT 33.770 102.575 34.310 102.855 ;
        RECT 35.150 102.575 35.690 102.855 ;
        RECT 36.530 102.575 37.070 102.855 ;
        RECT 37.910 102.575 38.450 102.855 ;
        RECT 39.290 102.575 39.830 102.855 ;
        RECT 40.670 102.575 41.210 102.855 ;
        RECT 42.050 102.575 42.590 102.855 ;
        RECT 43.430 102.575 43.970 102.855 ;
        RECT 44.810 102.575 45.350 102.855 ;
        RECT 46.190 102.575 46.730 102.855 ;
        RECT 47.570 102.575 48.110 102.855 ;
        RECT 48.950 102.575 49.490 102.855 ;
        RECT 50.330 102.575 50.870 102.855 ;
        RECT 51.710 102.575 52.250 102.855 ;
        RECT 53.090 102.575 53.630 102.855 ;
        RECT 54.470 102.575 55.010 102.855 ;
        RECT 55.850 102.575 56.390 102.855 ;
        RECT 57.230 102.575 57.770 102.855 ;
        RECT 58.610 102.575 59.150 102.855 ;
        RECT 59.990 102.575 60.530 102.855 ;
        RECT 61.370 102.575 61.910 102.855 ;
        RECT 62.750 102.575 63.290 102.855 ;
        RECT 64.130 102.575 64.670 102.855 ;
        RECT 65.510 102.575 66.050 102.855 ;
        RECT 66.890 102.575 67.430 102.855 ;
        RECT 68.270 102.575 68.810 102.855 ;
        RECT 69.650 102.575 70.190 102.855 ;
        RECT 71.030 102.575 71.570 102.855 ;
        RECT 72.410 102.575 72.950 102.855 ;
        RECT 73.790 102.575 74.330 102.855 ;
        RECT 75.170 102.575 75.710 102.855 ;
        RECT 76.550 102.575 77.090 102.855 ;
        RECT 77.930 102.575 78.470 102.855 ;
        RECT 79.310 102.575 79.850 102.855 ;
        RECT 80.690 102.575 81.230 102.855 ;
        RECT 82.070 102.575 82.610 102.855 ;
        RECT 83.450 102.575 83.990 102.855 ;
        RECT 84.830 102.575 85.370 102.855 ;
        RECT 86.210 102.575 86.750 102.855 ;
        RECT 87.590 102.575 88.130 102.855 ;
        RECT 88.970 102.575 89.510 102.855 ;
        RECT 90.350 102.575 90.890 102.855 ;
        RECT 91.730 102.575 93.740 102.855 ;
        RECT 2.400 4.280 93.740 102.575 ;
        RECT 2.950 0.155 4.870 4.280 ;
        RECT 5.710 0.155 7.630 4.280 ;
        RECT 8.470 0.155 10.390 4.280 ;
        RECT 11.230 0.155 13.150 4.280 ;
        RECT 13.990 0.155 15.910 4.280 ;
        RECT 16.750 0.155 18.670 4.280 ;
        RECT 19.510 0.155 21.430 4.280 ;
        RECT 22.270 0.155 24.190 4.280 ;
        RECT 25.030 0.155 26.950 4.280 ;
        RECT 27.790 0.155 29.710 4.280 ;
        RECT 30.550 0.155 32.470 4.280 ;
        RECT 33.310 0.155 35.230 4.280 ;
        RECT 36.070 0.155 37.990 4.280 ;
        RECT 38.830 0.155 40.750 4.280 ;
        RECT 41.590 0.155 43.510 4.280 ;
        RECT 44.350 0.155 46.270 4.280 ;
        RECT 47.110 0.155 49.030 4.280 ;
        RECT 49.870 0.155 51.790 4.280 ;
        RECT 52.630 0.155 54.550 4.280 ;
        RECT 55.390 0.155 57.310 4.280 ;
        RECT 58.150 0.155 60.070 4.280 ;
        RECT 60.910 0.155 62.830 4.280 ;
        RECT 63.670 0.155 65.590 4.280 ;
        RECT 66.430 0.155 68.350 4.280 ;
        RECT 69.190 0.155 71.110 4.280 ;
        RECT 71.950 0.155 73.870 4.280 ;
        RECT 74.710 0.155 76.630 4.280 ;
        RECT 77.470 0.155 79.390 4.280 ;
        RECT 80.230 0.155 82.150 4.280 ;
        RECT 82.990 0.155 84.910 4.280 ;
        RECT 85.750 0.155 87.670 4.280 ;
        RECT 88.510 0.155 90.430 4.280 ;
        RECT 91.270 0.155 93.190 4.280 ;
      LAYER met3 ;
        RECT 4.000 79.920 92.135 98.425 ;
        RECT 4.400 54.080 92.135 79.920 ;
        RECT 4.400 52.680 91.735 54.080 ;
        RECT 4.400 25.480 92.135 52.680 ;
        RECT 4.000 0.175 92.135 25.480 ;
      LAYER met4 ;
        RECT 12.255 95.840 80.665 97.065 ;
        RECT 12.255 26.695 20.640 95.840 ;
        RECT 23.040 26.695 23.940 95.840 ;
        RECT 26.340 26.695 80.665 95.840 ;
  END
END uart_ip
END LIBRARY

